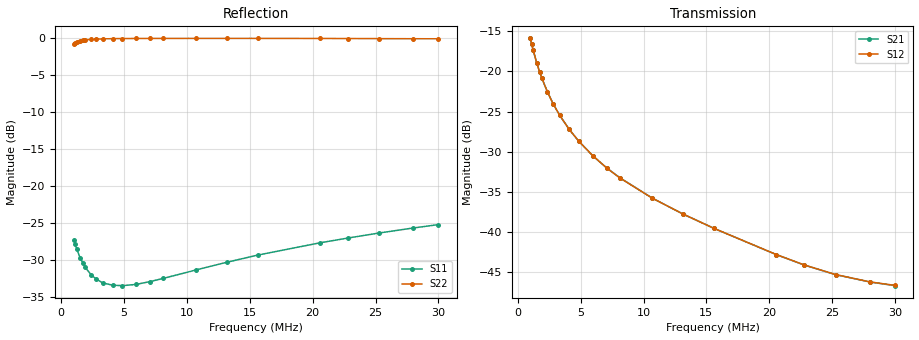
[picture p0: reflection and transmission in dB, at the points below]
! ListType=Log
!!FT114-61x2 13T CT Load
# MHZ S RI R 50
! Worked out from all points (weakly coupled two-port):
!   100 points, 1 MHz to 30 MHz, reference 50 ohm
!   highest |S21| = -15.88 dB at 1 MHz (marker M1); lowest = -46.7 dB at 30 MHz (marker M2)
!   lowest |S11| = -33.5 dB at 4.857 MHz (marker M3), VSWR 1.04, Z = 50.4 + j2.09 ohm
!   |S11| at or under -10 dB: start of sweep to end of sweep
!   |S22| runs from -0.7 to 0.0 dB; largest |S21 - S12| = 7.4e-05
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1  -0.0176 0.0398  0.0718 -0.1438  0.0718 -0.1438  0.7152 0.5747
1.108565  -0.0147 0.0377  0.0608 -0.1347  0.0607 -0.1346  0.7596 0.5378
1.228917  -0.0121 0.0358  0.0512 -0.1254  0.0511 -0.1254  0.7981 0.5001
1.510237  -0.00786 0.0319  0.0357 -0.1071  0.0357 -0.1071  0.8599 0.4262
1.732713  -0.0056 0.0296  0.0279 -0.0956  0.0279 -0.0956  0.8912 0.3794
1.920826  -0.00416 0.028  0.0231 -0.0875  0.0231 -0.0875  0.9102 0.3464
2.360535  -0.00173 0.0252  0.0157 -0.0728  0.0157 -0.0728  0.9397 0.2862
2.802932  -0.000139 0.0235  0.0114 -0.0621  0.0114 -0.062  0.9568 0.2421
3.32824  0.00134 0.0221  0.00823 -0.0527  0.00821 -0.0527  0.9694 0.2034
4.09013  0.00297 0.0212  0.00556 -0.0432  0.00555 -0.0432  0.9799 0.1635
4.856676  0.00425 0.0208  0.00402 -0.0365  0.00401 -0.0365  0.986 0.1349
5.968451  0.00603 0.0208  0.00273 -0.0297  0.00271 -0.0297  0.991 0.1053
7.087021  0.00769 0.0213  0.00198 -0.0249  0.00196 -0.0249  0.9938 0.0838
8.131027  0.00929 0.0219  0.00153 -0.0217  0.00152 -0.0216  0.9954 0.0683
10.70308  0.0133 0.0236  0.000948 -0.0162  0.00093 -0.0162  0.9974 0.0408
13.15319  0.0174 0.0251  0.000688 -0.0129  0.000677 -0.0129  0.998 0.0222
15.61828  0.0218 0.0263  0.000569 -0.0105  0.000565 -0.0105  0.9981 0.00738
20.55875  0.0314 0.0269  0.000699 -0.00719  0.000697 -0.0072  0.9966 -0.0163
22.79071  0.0359 0.0264  0.000922 -0.00615  0.000917 -0.00616  0.9952 -0.0252
25.26499  0.041 0.0253  0.00123 -0.00528  0.00123 -0.00529  0.9935 -0.0339
28.00789  0.0467 0.0232  0.00157 -0.00462  0.00156 -0.00463  0.9916 -0.0423
30  0.0507 0.0212  0.00176 -0.00428  0.00176 -0.0043  0.9905 -0.0478
